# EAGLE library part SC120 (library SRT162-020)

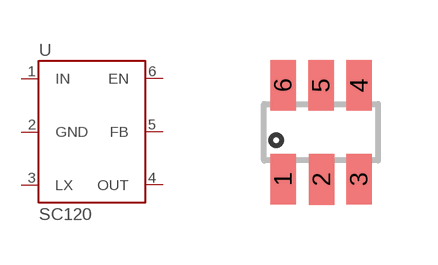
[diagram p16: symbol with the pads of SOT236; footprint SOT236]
Designator prefix U

## SC120  [SOT236]
1  IN  in
2  GND  pwr
3  LX  pas
4  OUT  out
5  FB  in
6  EN  in

## Footprint SOT236 (pad centres in mm)
smd 0.635 x 1.27: 1 -0.95,-1.175; 2 0.013,-1.185; 3 0.95,-1.175; 4 0.95,1.175; 5 0,1.175; 6 -0.95,1.175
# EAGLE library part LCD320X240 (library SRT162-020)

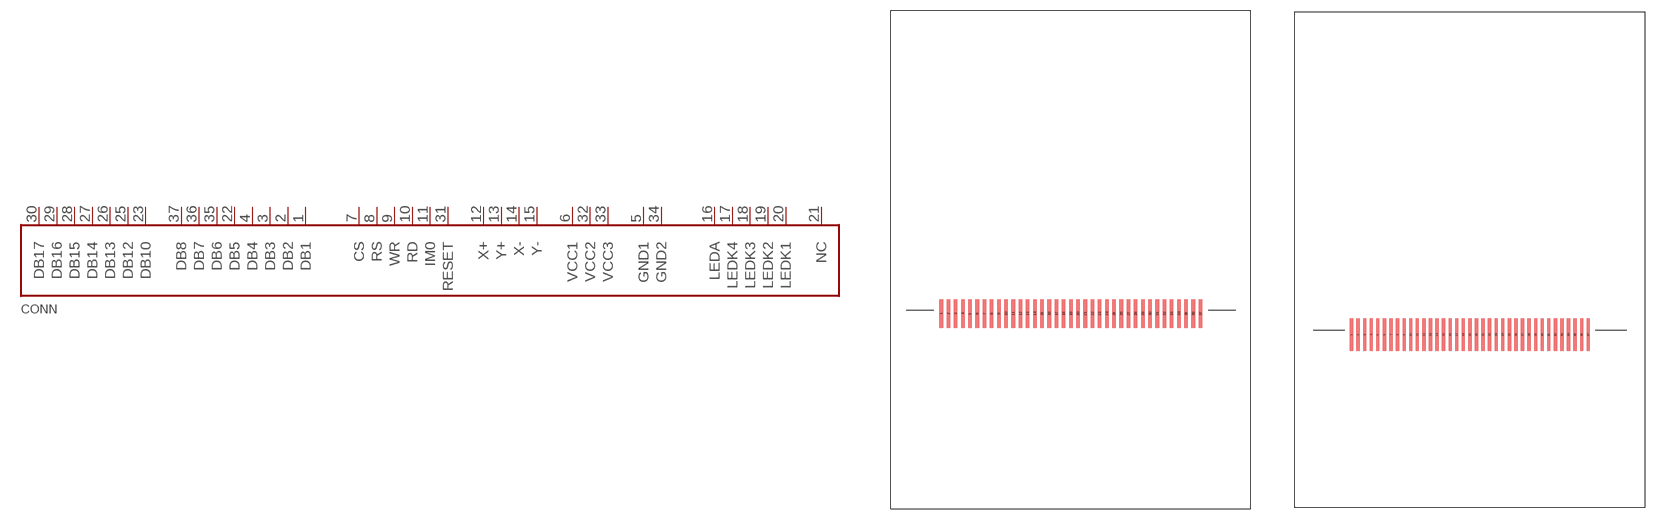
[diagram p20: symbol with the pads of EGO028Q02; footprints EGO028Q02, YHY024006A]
Designator prefix CONN

## LCD320X2402.8IN  [EGO028Q02]
1  DB1  pas
2  DB2  pas
3  DB3  pas
4  DB4  pas
5  GND1  pwr
6  VCC1  pwr
7  CS  pas
8  RS  pas
9  WR  pas
10  RD  pas
11  IM0  pas
12  X+  pas
13  Y+  pas
14  X-  pas
15  Y-  pas
16  LEDA  pas
17  LEDK4  pas
18  LEDK3  pas
19  LEDK2  pas
20  LEDK1  pas
21  NC  pas
22  DB5  pas
23  DB10  pas
24  DB11  pas
25  DB12  pas
26  DB13  pas
27  DB14  pas
28  DB15  pas
29  DB16  pas
30  DB17  pas
31  RESET  pas
32  VCC2  pwr
33  VCC3  pwr
34  GND2  pwr
35  DB6  pas
36  DB7  pas
37  DB8  pas

## LCD320X2402.4IN  [YHY024006A]
Pads as for EGO028Q02

## Footprint EGO028Q02 (pad centres in mm)
smd 0.5 x 4: 1 -18,0; 2 -17,0; 3 -16,0; 4 -15,0; 5 -14,0; 6 -13,0; 7 -12,0; 8 -11,0; 9 -10,0; 10 -9,0; 11 -8,0; 12 -7,0; 13 -6,0; 14 -5,0; 15 -4,0; 16 -3,0; 17 -2,0; 18 -1,0; 19 0,0; 20 1,0; 21 2,0; 22 3,0; 23 4,0; 24 5,0; 25 6,0; 26 7,0; 27 8,0; 28 9,0; 29 10,0; 30 11,0; 31 12,0; 32 13,0; 33 14,0; 34 15,0; 35 16,0; 36 17,0; 37 18,0

## Footprint YHY024006A (pad centres in mm)
smd 0.4 x 4: 1 -14.4,0; 2 -13.6,0; 3 -12.8,0; 4 -12,0; 5 -11.2,0; 6 -10.4,0; 7 -9.6,0; 8 -8.8,0; 9 -8,0; 10 -7.2,0; 11 -6.4,0; 12 -5.6,0; 13 -4.8,0; 14 -4,0; 15 -3.2,0; 16 -2.4,0; 17 -1.6,0; 18 -0.8,0; 19 0,0; 20 0.8,0; 21 1.6,0; 22 2.4,0; 23 3.2,0; 24 4,0; 25 4.8,0; 26 5.6,0; 27 6.4,0; 28 7.2,0; 29 8,0; 30 8.8,0; 31 9.6,0; 32 10.4,0; 33 11.2,0; 34 12,0; 35 12.8,0; 36 13.6,0; 37 14.4,0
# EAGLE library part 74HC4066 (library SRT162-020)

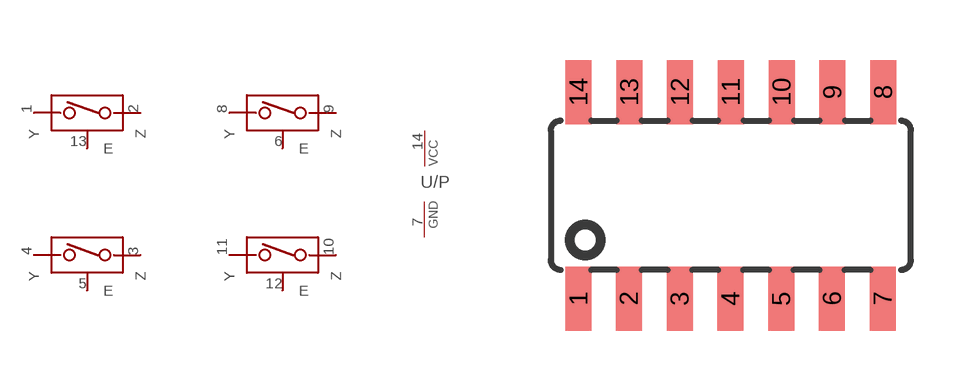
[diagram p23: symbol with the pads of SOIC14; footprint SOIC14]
Designator prefix U; gates /1=1/4_4066 /2=1/4_4066 /3=1/4_4066 /4=1/4_4066 /P=PWRN

## 74HC4066D  [SOIC14]
1  /1:Y  pas
2  /1:Z  pas
3  /2:Z  pas
4  /2:Y  pas
5  /2:E  in
6  /3:E  in
7  /P:GND  pwr
8  /3:Y  pas
9  /3:Z  pas
10  /4:Z  pas
11  /4:Y  pas
12  /4:E  in
13  /1:E  in
14  /P:VCC  pwr

## Footprint SOIC14 (pad centres in mm)
smd 0.65 x 1.6: 1 -5.715,-2.583; 2 -4.455,-2.583; 3 -3.185,-2.583; 4 -1.915,-2.583; 5 -0.645,-2.583; 6 0.625,-2.583; 7 1.895,-2.583; 8 1.905,2.583; 9 0.635,2.583; 10 -0.635,2.583; 11 -1.905,2.583; 12 -3.175,2.583; 13 -4.445,2.583; 14 -5.715,2.583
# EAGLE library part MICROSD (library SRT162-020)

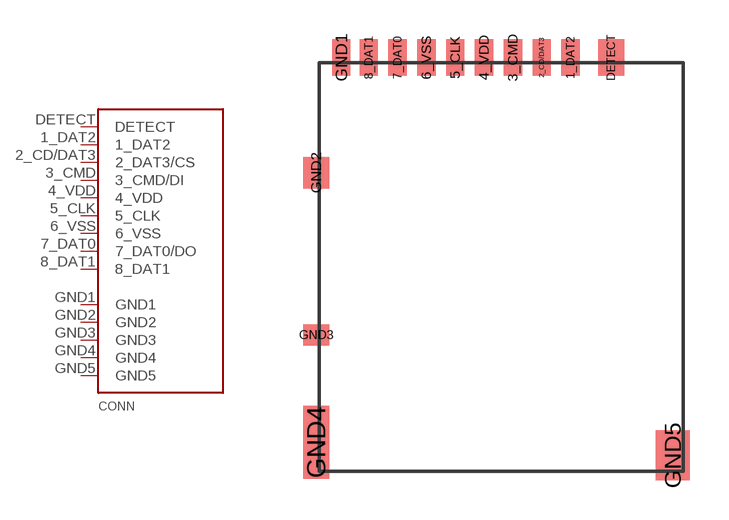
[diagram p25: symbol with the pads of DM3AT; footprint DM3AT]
Designator prefix CONN

## MICROSDDM3AT  [DM3AT]
1_DAT2  1_DAT2  pas
2_CD/DAT3  2_DAT3/CS  pas
3_CMD  3_CMD/DI  pas
4_VDD  4_VDD  pwr
5_CLK  5_CLK  pas
6_VSS  6_VSS  pwr
7_DAT0  7_DAT0/DO  pas
8_DAT1  8_DAT1  pas
DETECT  DETECT  pas
GND1  GND1  pas
GND2  GND2  pas
GND3  GND3  pas
GND4  GND4  pas
GND5  GND5  pas

## Footprint DM3AT (pad centres in mm)
smd 0.7 x 1.4: 1_DAT2 3.3,0.7; 2_CD/DAT3 2.2,0.7; 3_CMD 1.1,0.7; 4_VDD 0,0.7; 5_CLK -1.1,0.7; 6_VSS -2.2,0.7; 7_DAT0 -3.3,0.7; 8_DAT1 -4.4,0.7; GND1 -5.45,0.7
smd 1 x 1.4: DETECT 4.85,0.7
smd 1 x 1.2: GND2 -6.4,-3.7
smd 1 x 0.8: GND3 -6.4,-9.9
smd 1 x 2.8: GND4 -6.4,-14
smd 1.3 x 1.9: GND5 7.2,-14.5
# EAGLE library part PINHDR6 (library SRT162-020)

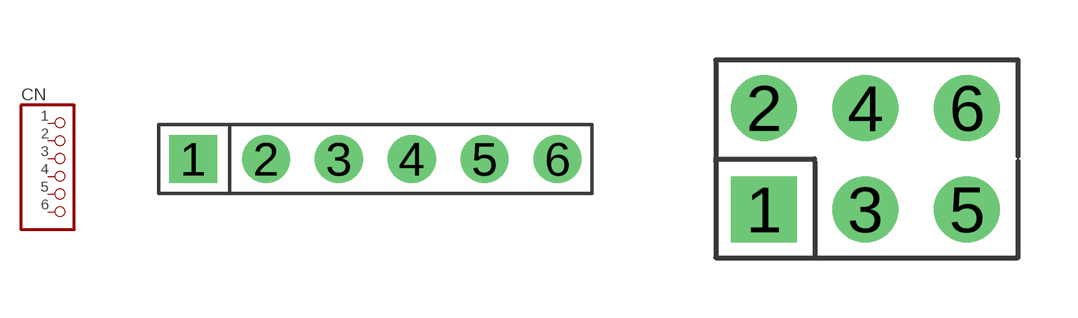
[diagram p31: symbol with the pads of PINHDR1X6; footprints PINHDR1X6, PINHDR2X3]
Designator prefix CN

## PINHDR6  [PINHDR1X6]
1  1  pas
2  2  pas
3  3  pas
4  4  pas
5  5  pas
6  6  pas

## PINHDR62X  [PINHDR2X3]
Pads as for PINHDR1X6

## PINHDR60.8  [PINHDR1X6_0.8]
Pads as for PINHDR1X6

## PINHDR60.8NM  [PINHDR1X6_0.8NM]
Pads as for PINHDR1X6

## PINHDR61.0  [PINHDR1X6_1.0]
Pads as for PINHDR1X6

## PINHDR61.0NM  [PINHDR1X6_1.0NM]
Pads as for PINHDR1X6

## PINHDR62MM  [PINHDR6_2MM]
Pads as for PINHDR1X6

## Footprint PINHDR1X6 (pad centres in mm)
drill 1.1 pad 1.676 square: 1 -6.35,0
drill 1.1 pad 1.676: 2 -3.81,0; 3 -1.27,0; 4 1.27,0; 5 3.81,0; 6 6.35,0

## Footprint PINHDR2X3 (pad centres in mm)
drill 1.1 square: 1 -2.54,-1.27
drill 1.1: 2 -2.54,1.27; 3 0,-1.27; 4 0,1.27; 5 2.54,-1.27; 6 2.54,1.27

## Footprint PINHDR1X6_0.8 (pad centres in mm)
drill 0.8 square: 1 -6.35,0
drill 0.8: 2 -3.81,0; 3 -1.27,0; 4 1.27,0; 5 3.81,0; 6 6.35,0

## Footprint PINHDR1X6_0.8NM (pad centres in mm)
drill 0.8: 1 -6.35,0; 2 -3.81,0; 3 -1.27,0; 4 1.27,0; 5 3.81,0; 6 6.35,0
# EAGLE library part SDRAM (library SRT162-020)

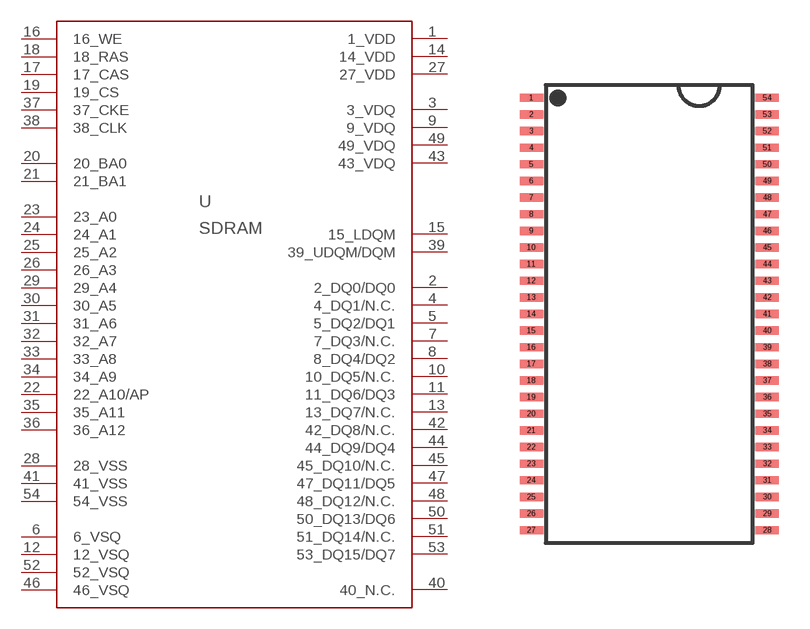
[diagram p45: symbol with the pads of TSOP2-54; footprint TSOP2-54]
Designator prefix U

## SDRAM  [TSOP2-54]
1  1_VDD  pwr
2  2_DQ0/DQ0
3  3_VDQ
4  4_DQ1/N.C.
5  5_DQ2/DQ1
6  6_VSQ  pwr
7  7_DQ3/N.C.
8  8_DQ4/DQ2
9  9_VDQ
10  10_DQ5/N.C.
11  11_DQ6/DQ3
12  12_VSQ  pwr
13  13_DQ7/N.C.
14  14_VDD  pwr
15  15_LDQM
16  16_WE  in
17  17_CAS  in
18  18_RAS  out
19  19_CS  in
20  20_BA0
21  21_BA1
22  22_A10/AP
23  23_A0
24  24_A1
25  25_A2
26  26_A3
27  27_VDD  pwr
28  28_VSS  pwr
29  29_A4
30  30_A5
31  31_A6
32  32_A7
33  33_A8
34  34_A9
35  35_A11
36  36_A12
37  37_CKE  in
38  38_CLK  in
39  39_UDQM/DQM  in
40  40_N.C.
41  41_VSS  pwr
42  42_DQ8/N.C.
43  43_VDQ
44  44_DQ9/DQ4
45  45_DQ10/N.C.
46  46_VSQ  pwr
47  47_DQ11/DQ5
48  48_DQ12/N.C.
49  49_VDQ
50  50_DQ13/DQ6
51  51_DQ14/N.C.
52  52_VSQ  pwr
53  53_DQ15/DQ7
54  54_VSS  pwr

## Footprint TSOP2-54 (pad centres in mm)
smd 1.1 x 0.4: 1 -5.68,10.4; 2 -5.68,9.6; 3 -5.68,8.8; 4 -5.68,8; 5 -5.68,7.2; 6 -5.68,6.4; 7 -5.68,5.6; 8 -5.68,4.8; 9 -5.68,4; 10 -5.68,3.2; 11 -5.68,2.4; 12 -5.68,1.6; 13 -5.68,0.8; 14 -5.68,0; 15 -5.68,-0.8; 16 -5.68,-1.6; 17 -5.68,-2.4; 18 -5.68,-3.2; 19 -5.68,-4; 20 -5.68,-4.8; 21 -5.68,-5.6; 22 -5.68,-6.4; 23 -5.68,-7.2; 24 -5.68,-8; 25 -5.68,-8.8; 26 -5.68,-9.6; 27 -5.68,-10.4; 28 5.68,-10.4; 29 5.68,-9.6; 30 5.68,-8.8; 31 5.68,-8; 32 5.68,-7.2; 33 5.68,-6.4; 34 5.68,-5.6; 35 5.68,-4.8; 36 5.68,-4; 37 5.68,-3.2; 38 5.68,-2.4; 39 5.68,-1.6; 40 5.68,-0.8; 41 5.68,0; 42 5.68,0.8; 43 5.68,1.6; 44 5.68,2.4; 45 5.68,3.2; 46 5.68,4; 47 5.68,4.8; 48 5.68,5.6; 49 5.68,6.4; 50 5.68,7.2; 51 5.68,8; 52 5.68,8.8; 53 5.68,9.6; 54 5.68,10.4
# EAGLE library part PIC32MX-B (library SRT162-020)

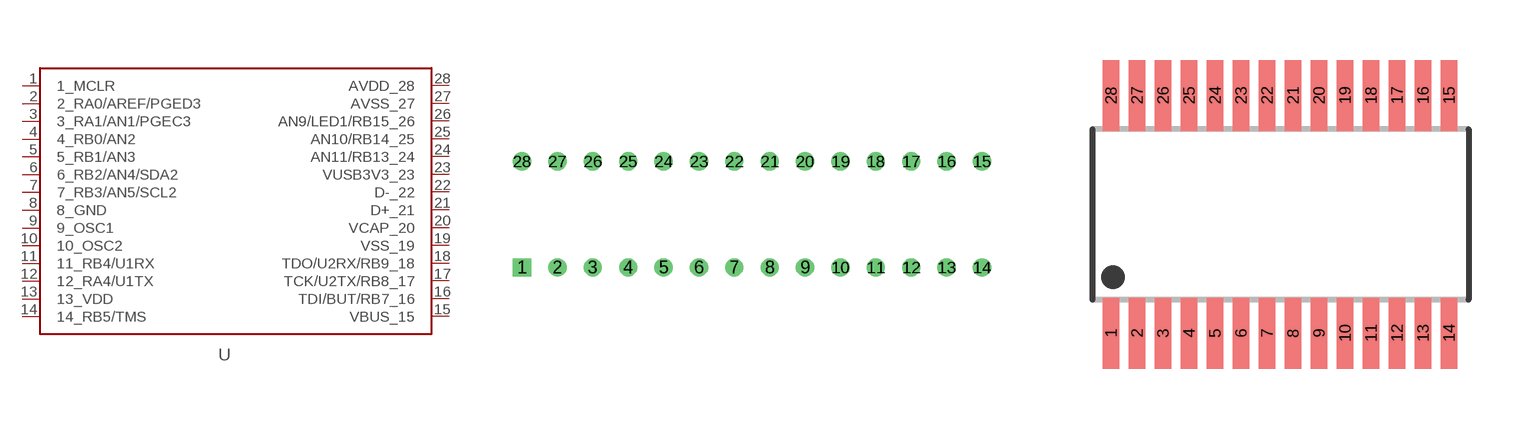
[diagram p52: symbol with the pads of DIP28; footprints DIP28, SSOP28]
Designator prefix U

## PIC32MX-BDIP  [DIP28]
1  1_MCLR  pas
2  2_RA0/AREF/PGED3  pas
3  3_RA1/AN1/PGEC3  pas
4  4_RB0/AN2  pas
5  5_RB1/AN3  pas
6  6_RB2/AN4/SDA2  pas
7  7_RB3/AN5/SCL2  pas
8  8_GND  pwr
9  9_OSC1  pas
10  10_OSC2  pas
11  11_RB4/U1RX  pas
12  12_RA4/U1TX  pas
13  13_VDD  pwr
14  14_RB5/TMS  pas
15  VBUS_15  pas
16  TDI/BUT/RB7_16  pas
17  TCK/U2TX/RB8_17  pas
18  TDO/U2RX/RB9_18  pas
19  VSS_19  pwr
20  VCAP_20  sup
21  D+_21  pas
22  D-_22  pas
23  VUSB3V3_23  pwr
24  AN11/RB13_24  pas
25  AN10/RB14_25  pas
26  AN9/LED1/RB15_26  pas
27  AVSS_27  pwr
28  AVDD_28  pwr

## PIC32MX-BSS  [SSOP28]
Pads as for DIP28

## PIC32MX-BQFN  [QFN28_0.65]
1  4_RB0/AN2  pas
2  5_RB1/AN3  pas
3  6_RB2/AN4/SDA2  pas
4  7_RB3/AN5/SCL2  pas
5  8_GND  pwr
6  9_OSC1  pas
7  10_OSC2  pas
8  11_RB4/U1RX  pas
9  12_RA4/U1TX  pas
10  13_VDD  pwr
11  14_RB5/TMS  pas
12  VBUS_15  pas
13  TDI/BUT/RB7_16  pas
14  TCK/U2TX/RB8_17  pas
15  TDO/U2RX/RB9_18  pas
16  VSS_19  pwr
17  VCAP_20  sup
18  D+_21  pas
19  D-_22  pas
20  VUSB3V3_23  pwr
21  AN11/RB13_24  pas
22  AN10/RB14_25  pas
23  AN9/LED1/RB15_26  pas
24  AVSS_27  pwr
25  AVDD_28  pwr
26  1_MCLR  pas
27  2_RA0/AREF/PGED3  pas
28  3_RA1/AN1/PGEC3  pas

## Footprint DIP28 (pad centres in mm)
drill 0.8 square: 1 -16.51,-3.81
drill 0.8: 2 -13.97,-3.81; 3 -11.43,-3.81; 4 -8.89,-3.81; 5 -6.35,-3.81; 6 -3.81,-3.81; 7 -1.27,-3.81; 8 1.27,-3.81; 9 3.81,-3.81; 10 6.35,-3.81; 11 8.89,-3.81; 12 11.43,-3.81; 13 13.97,-3.81; 14 16.51,-3.81; 15 16.51,3.81; 16 13.97,3.81; 17 11.43,3.81; 18 8.89,3.81; 19 6.35,3.81; 20 3.81,3.81; 21 1.27,3.81; 22 -1.27,3.81; 23 -3.81,3.81; 24 -6.35,3.81; 25 -8.89,3.81; 26 -11.43,3.81; 27 -13.97,3.81; 28 -16.51,3.81

## Footprint SSOP28 (pad centres in mm)
0.65mm pitch 28 pin
smd 0.42 x 1.78: 1 -4.26,-3.005; 2 -3.61,-3.005; 3 -2.96,-3.005; 4 -2.31,-3.005; 5 -1.66,-3.005; 6 -1.01,-3.005; 7 -0.36,-3.005; 8 0.29,-3.005; 9 0.94,-3.005; 10 1.59,-3.005; 11 2.24,-3.005; 12 2.89,-3.005; 13 3.54,-3.005; 14 4.19,-3.005; 15 4.19,2.945; 16 3.54,2.945; 17 2.89,2.945; 18 2.24,2.945; 19 1.59,2.945; 20 0.94,2.945; 21 0.29,2.945; 22 -0.36,2.945; 23 -1.01,2.945; 24 -1.66,2.945; 25 -2.31,2.945; 26 -2.96,2.945; 27 -3.61,2.945; 28 -4.26,2.945

## Footprint QFN28_0.65 (pad centres in mm)
smd 1.5 x 0.37: 1 -3.1,1.95; 2 -3.1,1.3; 3 -3.1,0.65; 4 -3.1,0; 5 -3.1,-0.65; 6 -3.1,-1.3; 7 -3.1,-1.95; 15 3.1,-1.95; 16 3.1,-1.3; 17 3.1,-0.65; 18 3.1,0; 19 3.1,0.65; 20 3.1,1.3; 21 3.1,1.95
smd 0.37 x 1.5: 8 -1.95,-3.1; 9 -1.3,-3.1; 10 -0.65,-3.1; 11 0,-3.1; 12 0.65,-3.1; 13 1.3,-3.1; 14 1.95,-3.1; 22 1.95,3.1; 23 1.3,3.1; 24 0.65,3.1; 25 0,3.1; 26 -0.65,3.1; 27 -1.3,3.1; 28 -1.95,3.1
drill 0.6 pad 1.6 octagon: PAD1 -0.9,0.9
drill 0.6 pad 1.6 square: PAD2 -0.9,-0.9; PAD3 0.9,-0.9; PAD4 0.9,0.9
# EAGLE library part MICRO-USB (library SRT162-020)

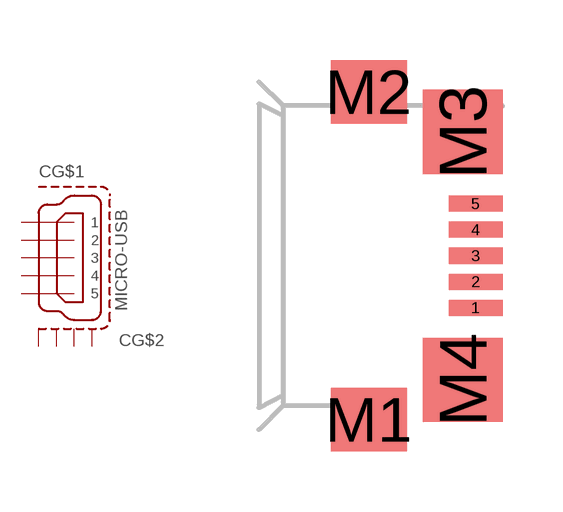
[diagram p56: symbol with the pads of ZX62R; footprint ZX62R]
Designator prefix C; gates G$1=MINI-USB G$2=USB-SHIELD

## MICRO-USB  [ZX62R]
1  G$1:1
2  G$1:2
3  G$1:3
4  G$1:4
5  G$1:5
M1  G$2:S1  pas
M2  G$2:S2  pas
M3  G$2:S3  pas
M4  G$2:S4  pas

## Footprint ZX62R (pad centres in mm)
smd 1.35 x 0.4: 1 2.675,-1.3; 2 2.675,-0.65; 3 2.675,0; 4 2.675,0.65; 5 2.675,1.3
smd 1.9 x 1.6: M1 0,-4.1; M2 0,4.1
smd 2 x 2.1: M3 2.35,3.1; M4 2.35,-3.1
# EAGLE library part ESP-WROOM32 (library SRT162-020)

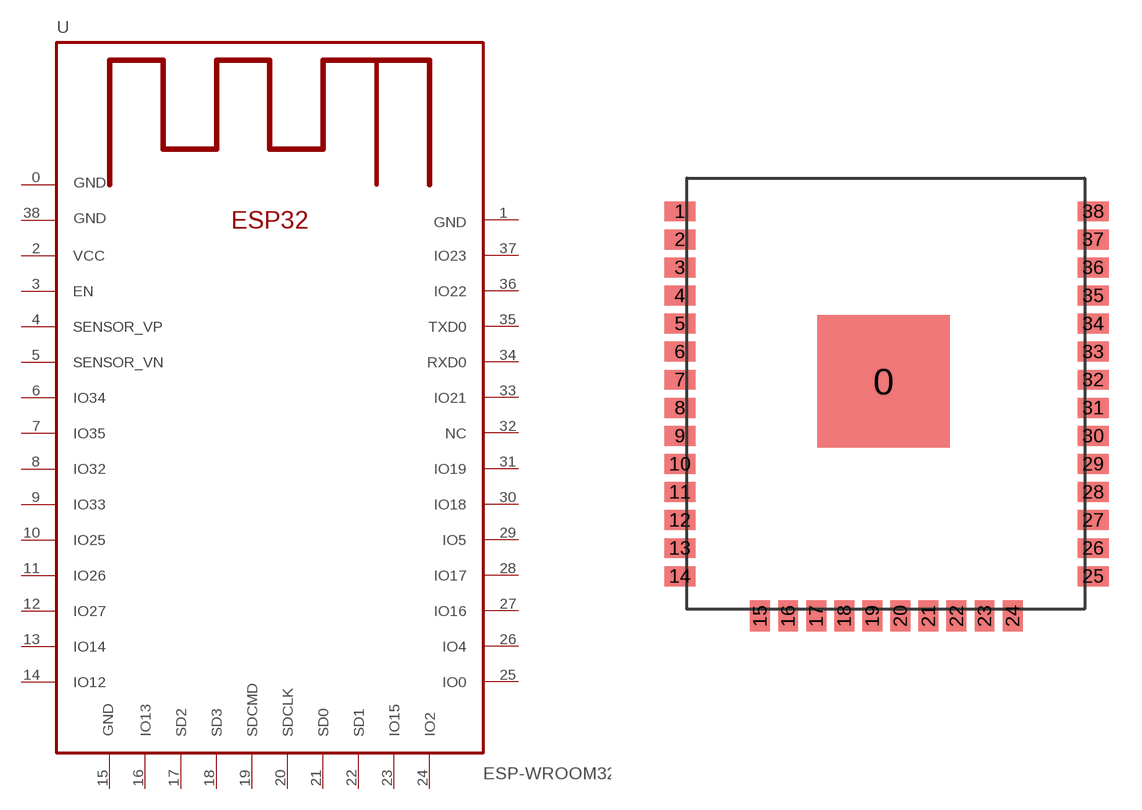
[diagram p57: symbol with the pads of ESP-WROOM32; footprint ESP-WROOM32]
Designator prefix U

## ESP-WROOM32  [ESP-WROOM32]
0  GND  pwr
1  GND  pwr
2  VCC  pwr
3  EN
4  SENSOR_VP
5  SENSOR_VN
6  IO34
7  IO35
8  IO32
9  IO33
10  IO25
11  IO26
12  IO27
13  IO14
14  IO12
15  GND  pwr
16  IO13
17  SD2
18  SD3
19  SDCMD
20  SDCLK
21  SD0
22  SD1
23  IO15
24  IO2
25  IO0
26  IO4
27  IO16
28  IO17
29  IO5
30  IO18
31  IO19
32  NC
33  IO21
34  RXD0
35  TXD0
36  IO22
37  IO23
38  GND  pwr

## Footprint ESP-WROOM32 (pad centres in mm)
smd 6 x 6: 0 9.9,12.3
smd 1.4 x 0.9: 1 0.68,19.99; 2 0.68,18.72; 3 0.68,17.45; 4 0.68,16.18; 5 0.68,14.91; 6 0.68,13.64; 7 0.68,12.37; 8 0.68,11.1; 9 0.68,9.83; 10 0.68,8.56; 11 0.68,7.29; 12 0.68,6.02; 13 0.68,4.75; 14 0.68,3.48; 25 19.38,3.48; 26 19.38,4.75; 27 19.38,6.02; 28 19.38,7.29; 29 19.38,8.56; 30 19.38,9.83; 31 19.38,11.1; 32 19.38,12.37; 33 19.38,13.64; 34 19.38,14.91; 35 19.38,16.18; 36 19.38,17.45; 37 19.38,18.72; 38 19.38,19.99
smd 0.9 x 1.4: 15 4.31,1.68; 16 5.58,1.68; 17 6.85,1.68; 18 8.12,1.68; 19 9.39,1.68; 20 10.66,1.68; 21 11.93,1.68; 22 13.2,1.68; 23 14.47,1.68; 24 15.74,1.68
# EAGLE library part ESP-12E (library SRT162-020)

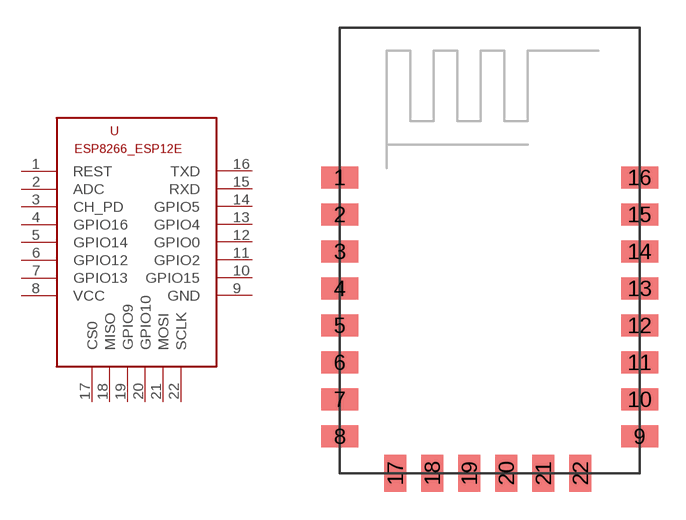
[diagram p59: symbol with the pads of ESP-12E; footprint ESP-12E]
Designator prefix -

## ESP-12E  [ESP-12E]
1  REST
2  ADC
3  CH_PD
4  GPIO16
5  GPIO14
6  GPIO12
7  GPIO13
8  VCC
9  GND
10  GPIO15
11  GPIO2
12  GPIO0
13  GPIO4
14  GPIO5
15  RXD
16  TXD
17  CS0
18  MISO
19  GPIO9
20  GPIO10
21  MOSI
22  SCLK

## Footprint ESP-12E (pad centres in mm)
smd 2 x 1.2: 1 -7.62,5.84; 2 -7.62,3.84; 3 -7.62,1.84; 4 -7.62,-0.16; 5 -7.62,-2.16; 6 -7.62,-4.16; 7 -7.62,-6.16; 8 -7.62,-8.16; 9 8.58,-8.16; 10 8.58,-6.16; 11 8.58,-4.16; 12 8.58,-2.16; 13 8.58,-0.16; 14 8.58,1.84; 15 8.58,3.84; 16 8.58,5.84
smd 1.2 x 2: 17 -4.62,-10.16; 18 -2.62,-10.16; 19 -0.62,-10.16; 20 1.38,-10.16; 21 3.38,-10.16; 22 5.38,-10.16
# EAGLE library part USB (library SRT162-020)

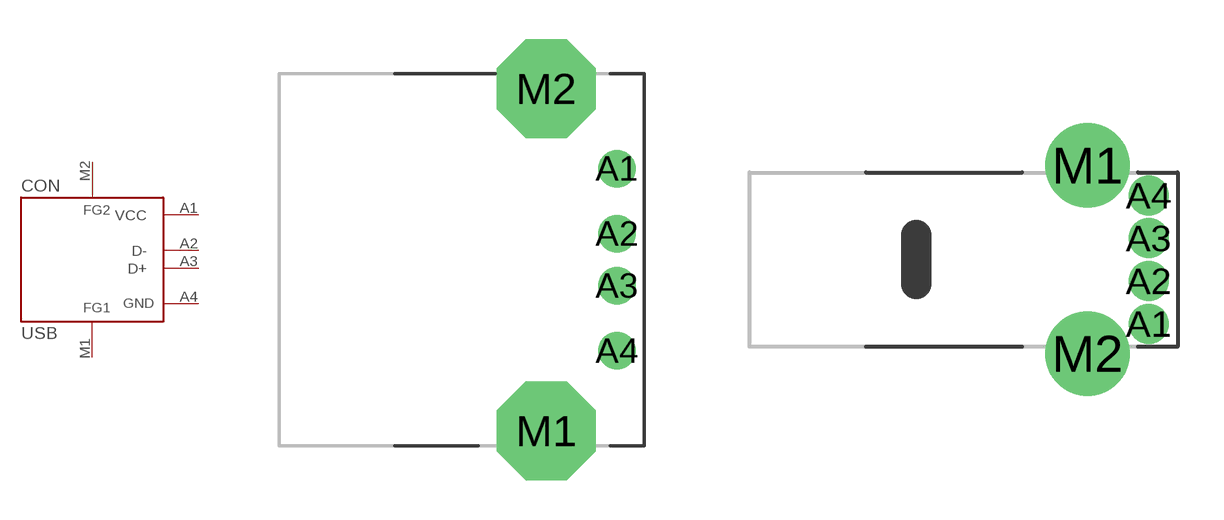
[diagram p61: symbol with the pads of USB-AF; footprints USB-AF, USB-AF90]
Designator prefix CON

## USB-B  [USB-AF]
A1  VCC  pas
A2  D-
A3  D+
A4  GND  pas
M1  GND  pas
M2  GND  pas

## USB90  [USB-AF90]
Pads as for USB-AF

## Footprint USB-AF (pad centres in mm)
drill 0.93: A1 3.175,3.5; A2 3.175,1; A3 3.175,-1; A4 3.175,-3.5
drill 2.4 pad 3.81 octagon: M1 0.465,-6.57; M2 0.465,6.57

## Footprint USB-AF90 (pad centres in mm)
drill 0.8 pad 1.156: A1 2,-2.1; A2 2,-0.7; A3 2,0.7; A4 2,2.1
drill 1.84 pad 2.348: M1 0,3.08; M2 0,-3.08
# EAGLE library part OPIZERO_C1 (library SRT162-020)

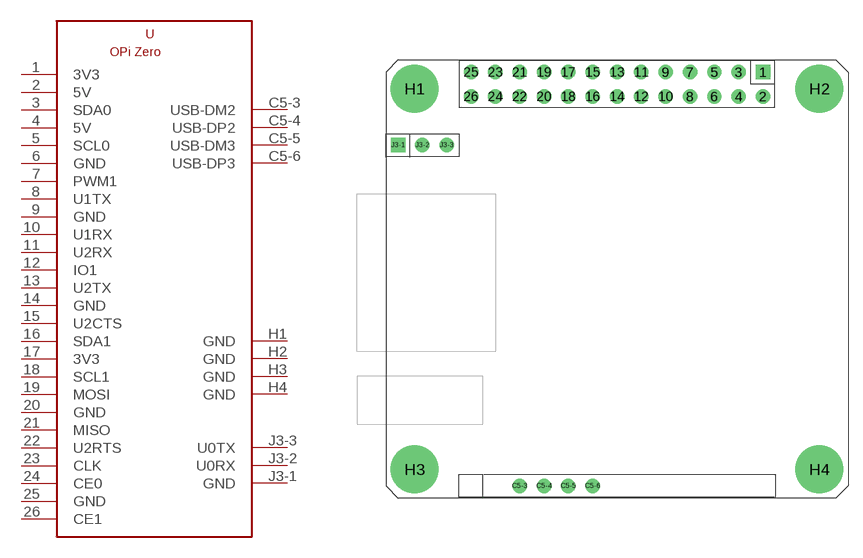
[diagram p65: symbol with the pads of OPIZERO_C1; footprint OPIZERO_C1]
Designator prefix -

## OPIZERO_C1  [OPIZERO_C1]
1  3V3
2  5V  pwr
3  SDA0
4  5V  pwr
5  SCL0
6  GND  pwr
7  PWM1
8  U1TX
9  GND  pwr
10  U1RX
11  U2RX
12  IO1
13  U2TX
14  GND  pwr
15  U2CTS
16  SDA1
17  3V3
18  SCL1
19  MOSI
20  GND  pwr
21  MISO
22  U2RTS
23  CLK
24  CE0
25  GND  pwr
26  CE1
C5-3  USB-DM2
C5-4  USB-DP2
C5-5  USB-DM3
C5-6  USB-DP3
H1  GND  pwr
H2  GND  pwr
H3  GND  pwr
H4  GND  pwr
J3-1  GND  pwr
J3-2  U0RX
J3-3  U0TX

## Footprint OPIZERO_C1 (pad centres in mm)
drill 1 square: 1 15.24,21.59; J3-1 -22.86,13.97
drill 1: 2 15.24,19.05; 3 12.7,21.59; 4 12.7,19.05; 5 10.16,21.59; 6 10.16,19.05; 7 7.62,21.59; 8 7.62,19.05; 9 5.08,21.59; 10 5.08,19.05; 11 2.54,21.59; 12 2.54,19.05; 13 0,21.59; 14 0,19.05; 15 -2.54,21.59; 16 -2.54,19.05; 17 -5.08,21.59; 18 -5.08,19.05; 19 -7.62,21.59; 20 -7.62,19.05; 21 -10.16,21.59; 22 -10.16,19.05; 23 -12.7,21.59; 24 -12.7,19.05; 25 -15.24,21.59; 26 -15.24,19.05; C5-3 -10.16,-21.59; C5-4 -7.62,-21.59; C5-5 -5.08,-21.59; C5-6 -2.54,-21.59; J3-2 -20.32,13.97; J3-3 -17.78,13.97
drill 3.3 pad 5: H1 -21.13,19.86; H2 21.13,19.86; H3 -21.13,-19.86; H4 21.13,-19.86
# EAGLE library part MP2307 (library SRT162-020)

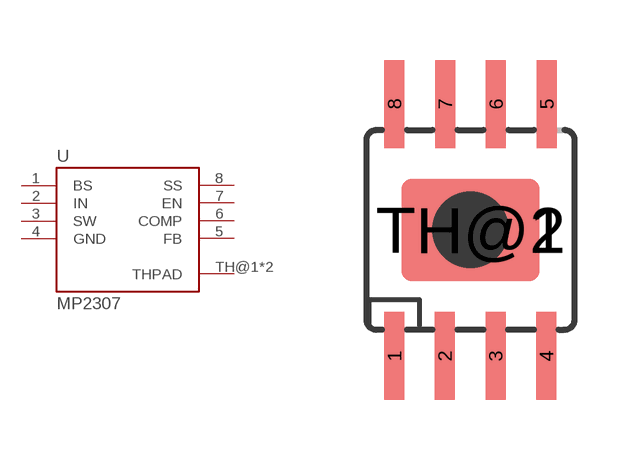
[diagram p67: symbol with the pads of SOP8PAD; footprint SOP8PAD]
Designator prefix -

## MP2307  [SOP8PAD]
1  BS
2  IN
3  SW
4  GND  pas
5  FB
6  COMP
7  EN
8  SS
TH@1  THPAD  pas
TH@2  THPAD  pas

## Footprint SOP8PAD (pad centres in mm)
smd 0.5 x 2.2: 1 -1.905,-3.154; 2 -0.645,-3.154; 3 0.625,-3.154; 4 1.895,-3.154; 5 1.905,3.154; 6 0.635,3.154; 7 -0.635,3.154; 8 -1.905,3.154
smd 3.454 x 2.565: TH@1 0,0
smd 3.454 x 2.565 bottom: TH@2 0,0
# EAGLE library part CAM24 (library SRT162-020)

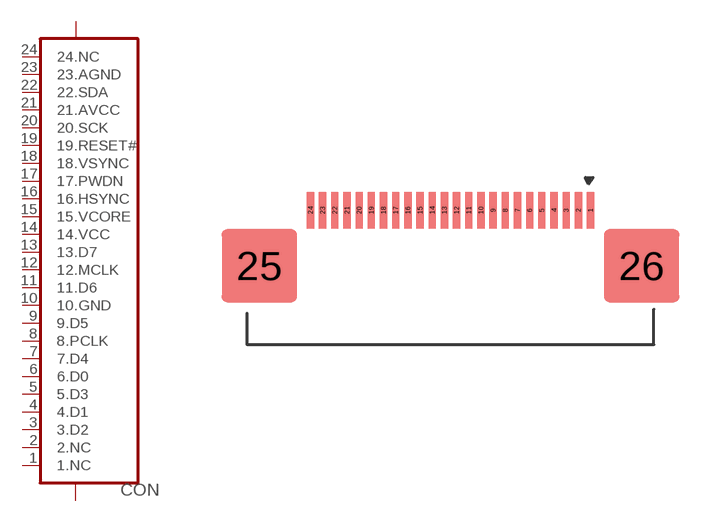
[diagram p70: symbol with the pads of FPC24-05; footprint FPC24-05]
Designator prefix CON

## CAM24  [FPC24-05]
1  1.NC  pas
2  2.NC  pas
3  3.D2  pas
4  4.D1  pas
5  5.D3  pas
6  6.D0  pas
7  7.D4  pas
8  8.PCLK  pas
9  9.D5  pas
10  10.GND  pas
11  11.D6  pas
12  12.MCLK  pas
13  13.D7  pas
14  14.VCC  pas
15  15.VCORE  pas
16  16.HSYNC  pas
17  17.PWDN  pas
18  18.VSYNC  pas
19  19.RESET#  pas
20  20.SCK  pas
21  21.AVCC  pas
22  22.SDA  pas
23  23.AGND  pas
24  24.NC  pas
25  25  pas
26  26  pas

## Footprint FPC24-05 (pad centres in mm)
smd 0.3 x 1.5: 1 5.75,-0.7; 2 5.25,-0.7; 3 4.75,-0.7; 4 4.25,-0.7; 5 3.75,-0.7; 6 3.25,-0.7; 7 2.75,-0.7; 8 2.25,-0.7; 9 1.75,-0.7; 10 1.25,-0.7; 11 0.75,-0.7; 12 0.25,-0.7; 13 -0.25,-0.7; 14 -0.75,-0.7; 15 -1.25,-0.7; 16 -1.75,-0.7; 17 -2.25,-0.7; 18 -2.75,-0.7; 19 -3.25,-0.7; 20 -3.75,-0.7; 21 -4.25,-0.7; 22 -4.75,-0.7; 23 -5.25,-0.7; 24 -5.75,-0.7
smd 3.1 x 3: 25 -7.85,-2.98; 26 7.85,-2.98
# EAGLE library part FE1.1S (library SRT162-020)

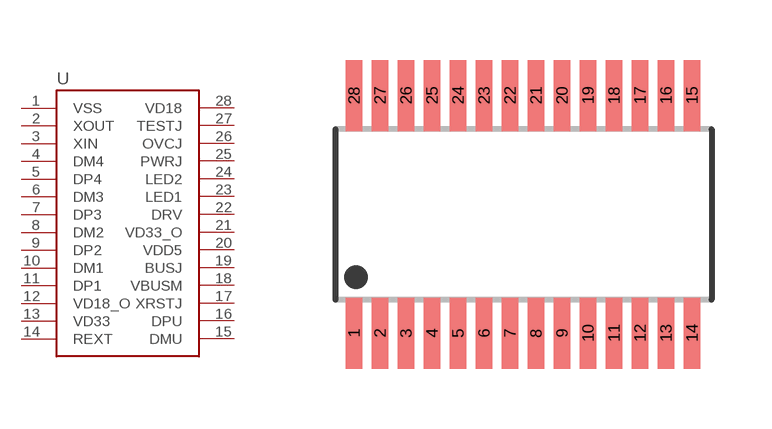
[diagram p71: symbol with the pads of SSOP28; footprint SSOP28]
Designator prefix U

## FE1.1S  [SSOP28]
1  VSS
2  XOUT
3  XIN
4  DM4
5  DP4
6  DM3
7  DP3
8  DM2
9  DP2
10  DM1
11  DP1
12  VD18_O
13  VD33
14  REXT
15  DMU
16  DPU
17  XRSTJ
18  VBUSM
19  BUSJ
20  VDD5
21  VD33_O
22  DRV
23  LED1
24  LED2
25  PWRJ
26  OVCJ
27  TESTJ
28  VD18

## Footprint SSOP28 (pad centres in mm)
0.65mm pitch 28 pin
smd 0.42 x 1.78: 1 -4.26,-3.005; 2 -3.61,-3.005; 3 -2.96,-3.005; 4 -2.31,-3.005; 5 -1.66,-3.005; 6 -1.01,-3.005; 7 -0.36,-3.005; 8 0.29,-3.005; 9 0.94,-3.005; 10 1.59,-3.005; 11 2.24,-3.005; 12 2.89,-3.005; 13 3.54,-3.005; 14 4.19,-3.005; 15 4.19,2.945; 16 3.54,2.945; 17 2.89,2.945; 18 2.24,2.945; 19 1.59,2.945; 20 0.94,2.945; 21 0.29,2.945; 22 -0.36,2.945; 23 -1.01,2.945; 24 -1.66,2.945; 25 -2.31,2.945; 26 -2.96,2.945; 27 -3.61,2.945; 28 -4.26,2.945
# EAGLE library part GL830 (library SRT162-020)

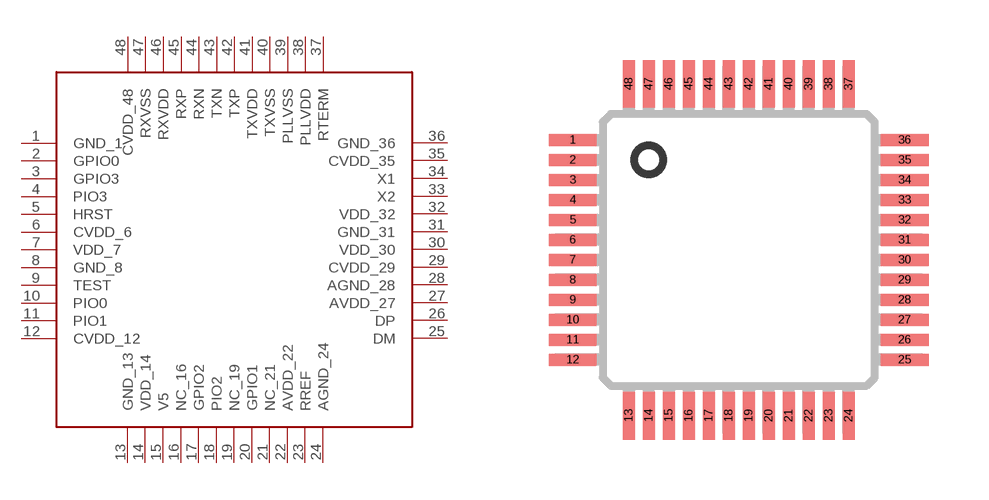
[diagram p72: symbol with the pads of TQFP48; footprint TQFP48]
Designator prefix U

## GL830  [TQFP48]
1  GND_1
2  GPIO0
3  GPIO3
4  PIO3
5  HRST
6  CVDD_6
7  VDD_7
8  GND_8
9  TEST
10  PIO0
11  PIO1
12  CVDD_12
13  GND_13
14  VDD_14
15  V5
16  NC_16
17  GPIO2
18  PIO2
19  NC_19
20  GPIO1
21  NC_21
22  AVDD_22
23  RREF
24  AGND_24
25  DM
26  DP
27  AVDD_27
28  AGND_28
29  CVDD_29
30  VDD_30
31  GND_31
32  VDD_32
33  X2
34  X1
35  CVDD_35
36  GND_36
37  RTERM
38  PLLVDD
39  PLLVSS
40  TXVSS
41  TXVDD
42  TXP
43  TXN
44  RXN
45  RXP
46  RXVDD
47  RXVSS
48  CVDD_48

## Footprint TQFP48 (pad centres in mm)
smd 1.2 x 0.3: 1 -4.15,2.75; 2 -4.15,2.25; 3 -4.15,1.75; 4 -4.15,1.25; 5 -4.15,0.75; 6 -4.15,0.25; 7 -4.15,-0.25; 8 -4.15,-0.75; 9 -4.15,-1.25; 10 -4.15,-1.75; 11 -4.15,-2.25; 12 -4.15,-2.75; 25 4.15,-2.75; 26 4.15,-2.25; 27 4.15,-1.75; 28 4.15,-1.25; 29 4.15,-0.75; 30 4.15,-0.25; 31 4.15,0.25; 32 4.15,0.75; 33 4.15,1.25; 34 4.15,1.75; 35 4.15,2.25; 36 4.15,2.75
smd 0.3 x 1.2: 13 -2.75,-4.15; 14 -2.25,-4.15; 15 -1.75,-4.15; 16 -1.25,-4.15; 17 -0.75,-4.15; 18 -0.25,-4.15; 19 0.25,-4.15; 20 0.75,-4.15; 21 1.25,-4.15; 22 1.75,-4.15; 23 2.25,-4.15; 24 2.75,-4.15; 37 2.75,4.15; 38 2.25,4.15; 39 1.75,4.15; 40 1.25,4.15; 41 0.75,4.15; 42 0.25,4.15; 43 -0.25,4.15; 44 -0.75,4.15; 45 -1.25,4.15; 46 -1.75,4.15; 47 -2.25,4.15; 48 -2.75,4.15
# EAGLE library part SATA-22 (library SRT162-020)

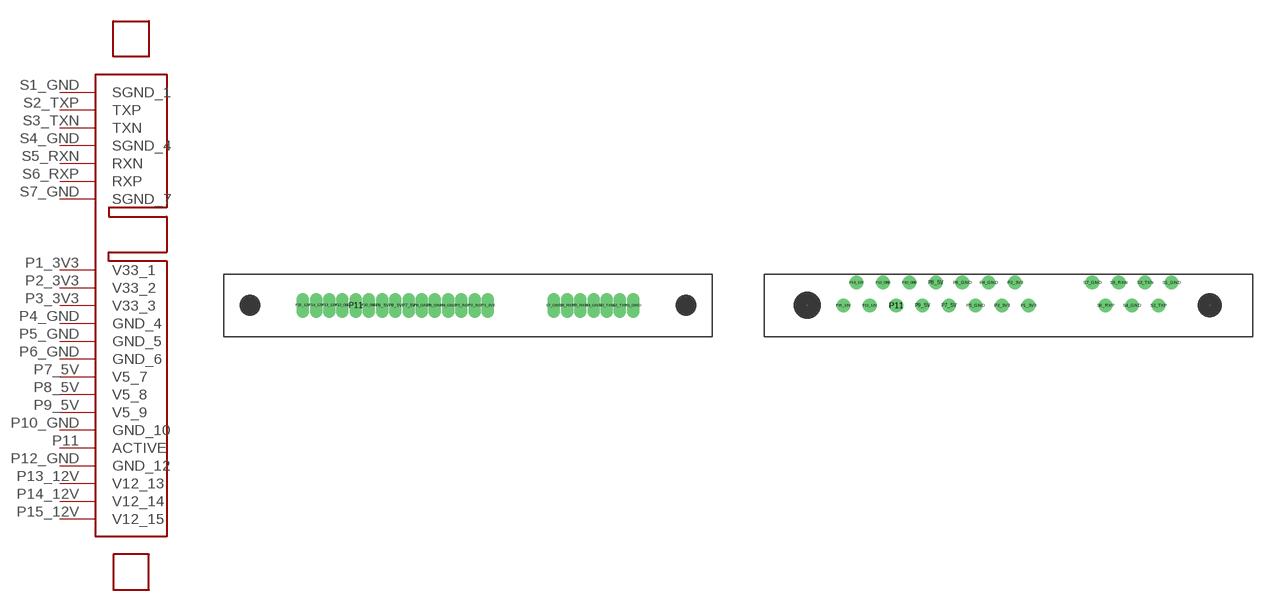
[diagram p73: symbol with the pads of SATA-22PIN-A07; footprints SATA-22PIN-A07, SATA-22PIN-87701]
Designator prefix CON

## SATA-22-07  [SATA-22PIN-A07]
P1_3V3  V33_1
P2_3V3  V33_2
P3_3V3  V33_3
P4_GND  GND_4
P5_GND  GND_5
P6_GND  GND_6
P7_5V  V5_7
P8_5V  V5_8
P9_5V  V5_9
P10_GND  GND_10
P11  ACTIVE
P12_GND  GND_12
P13_12V  V12_13
P14_12V  V12_14
P15_12V  V12_15
S1_GND  SGND_1
S2_TXP  TXP
S3_TXN  TXN
S4_GND  SGND_4
S5_RXN  RXN
S6_RXP  RXP
S7_GND  SGND_7

## SATA-22  [SATA-22PIN-87701]
Pads as for SATA-22PIN-A07

## SATA-2279  [SATA-22PIN-87779]
Pads as for SATA-22PIN-A07

## Footprint SATA-22PIN-A07 (pad centres in mm)
drill 0.7 pad 1.081 long: P1_3V3 0,0; P2_3V3 -1.27,0; P3_3V3 -2.54,0; P4_GND -3.81,0; P5_GND -5.08,0; P6_GND -6.35,0; P7_5V -7.62,0; P8_5V -8.89,0; P9_5V -10.16,0; P10_GND -11.43,0; P11 -12.7,0; P12_GND -13.97,0; P13_12V -15.24,0; P14_12V -16.51,0; P15_12V -17.78,0; S1_GND 13.97,0; S2_TXP 12.7,0; S3_TXN 11.43,0; S4_GND 10.16,0; S5_RXN 8.89,0; S6_RXP 7.62,0; S7_GND 6.35,0

## Footprint SATA-22PIN-87701 (pad centres in mm)
drill 0.8 pad 1.081: P1_3V3 0,0; P2_3V3 -1.27,2.2; P3_3V3 -2.54,0; P4_GND -3.81,2.2; P5_GND -5.08,0; P6_GND -6.35,2.2; P7_5V -7.62,0; P8_5V -8.89,2.2; P9_5V -10.16,0; P10_GND -11.43,2.2; P11 -12.7,0; P12_GND -13.97,2.2; P13_12V -15.24,0; P14_12V -16.51,2.2; P15_12V -17.78,0; S1_GND 13.77,2.2; S2_TXP 12.5,0; S3_TXN 11.23,2.2; S4_GND 9.96,0; S5_RXN 8.69,2.2; S6_RXP 7.42,0; S7_GND 6.15,2.2

## Footprint SATA-22PIN-87779 (pad centres in mm)
drill 0.7 pad 1.081 long: P1_3V3 0,0; P2_3V3 -1.27,0; P3_3V3 -2.54,0; P4_GND -3.81,0; P5_GND -5.08,0; P6_GND -6.35,0; P7_5V -7.62,0; P8_5V -8.89,0; P9_5V -10.16,0; P10_GND -11.43,0; P11 -12.7,0; P12_GND -13.97,0; P13_12V -15.24,0; P14_12V -16.51,0; P15_12V -17.78,0; S1_GND 13.77,0; S2_TXP 12.5,0; S3_TXN 11.23,0; S4_GND 9.96,0; S5_RXN 8.69,0; S6_RXP 7.42,0; S7_GND 6.15,0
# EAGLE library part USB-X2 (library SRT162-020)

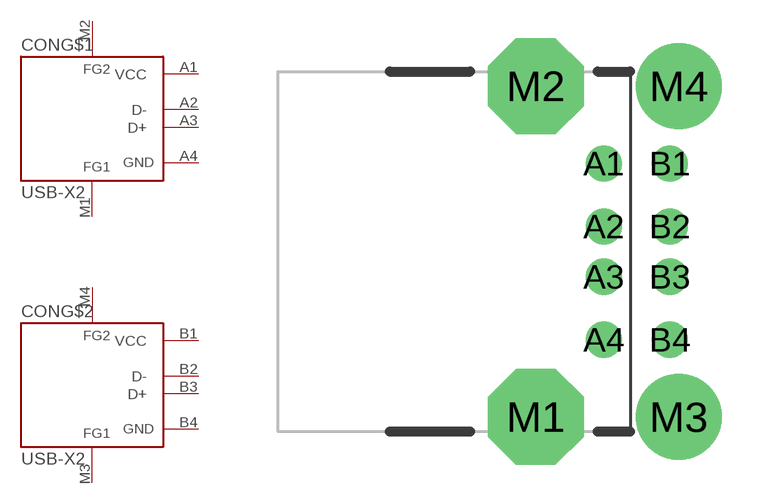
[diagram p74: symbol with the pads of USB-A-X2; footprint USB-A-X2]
Designator prefix CON; gates G$1=USB G$2=USB

## USB-X2  [USB-A-X2]
A1  G$1:VCC  pas
A2  G$1:D-
A3  G$1:D+
A4  G$1:GND  pas
B1  G$2:VCC  pas
B2  G$2:D-
B3  G$2:D+
B4  G$2:GND  pas
M1  G$1:GND  pas
M2  G$1:GND  pas
M3  G$2:GND  pas
M4  G$2:GND  pas

## Footprint USB-A-X2 (pad centres in mm)
drill 0.93 pad 1.438: A1 3.175,3.5; A2 3.175,1; A3 3.175,-1; A4 3.175,-3.5; B1 5.795,3.5; B2 5.795,1; B3 5.795,-1; B4 5.795,-3.5
drill 2.4 pad 3.81 octagon: M1 0.465,-6.57; M2 0.465,6.57
drill 2.4 pad 2.918: M3 6.145,-6.57
drill 2.4 pad 2.908: M4 6.145,6.57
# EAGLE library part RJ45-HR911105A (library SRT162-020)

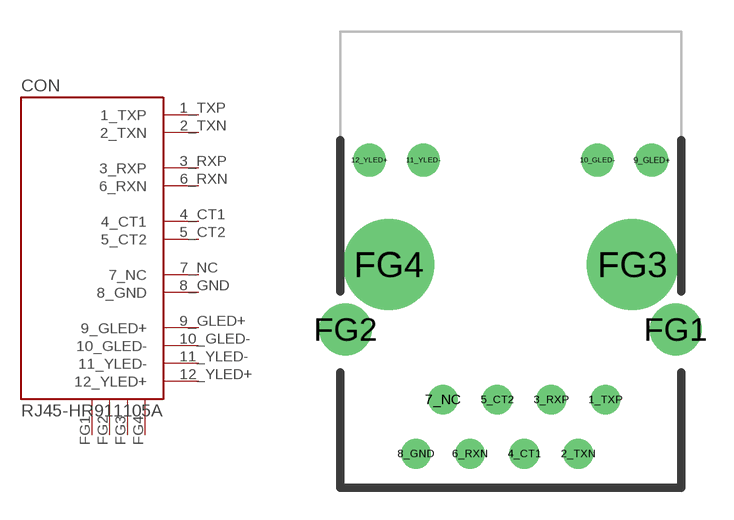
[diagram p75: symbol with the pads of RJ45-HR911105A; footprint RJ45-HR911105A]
Designator prefix CON

## RJ45-HR911105A  [RJ45-HR911105A]
1_TXP  1_TXP
2_TXN  2_TXN
3_RXP  3_RXP
4_CT1  4_CT1
5_CT2  5_CT2
6_RXN  6_RXN
7_NC  7_NC  pas
8_GND  8_GND  pas
9_GLED+  9_GLED+
10_GLED-  10_GLED-
11_YLED-  11_YLED-
12_YLED+  12_YLED+
FG1  GND  pas
FG2  GND  pas
FG3  GND  pas
FG4  GND  pas

## Footprint RJ45-HR911105A (pad centres in mm)
drill 0.89: 1_TXP 4.45,-6.35; 2_TXN 3.18,-8.89; 3_RXP 1.91,-6.35; 4_CT1 0.64,-8.89; 5_CT2 -0.63,-6.35; 6_RXN -1.9,-8.89; 7_NC -3.17,-6.35; 8_GND -4.44,-8.89
drill 1.02 pad 1.528: 9_GLED+ 6.625,4.9; 10_GLED- 4.085,4.9; 11_YLED- -4.085,4.9; 12_YLED+ -6.625,4.9
drill 1.63: FG1 7.745,-3.05; FG2 -7.745,-3.05
drill 3.25 pad 3.75: FG3 5.715,0; FG4 -5.715,0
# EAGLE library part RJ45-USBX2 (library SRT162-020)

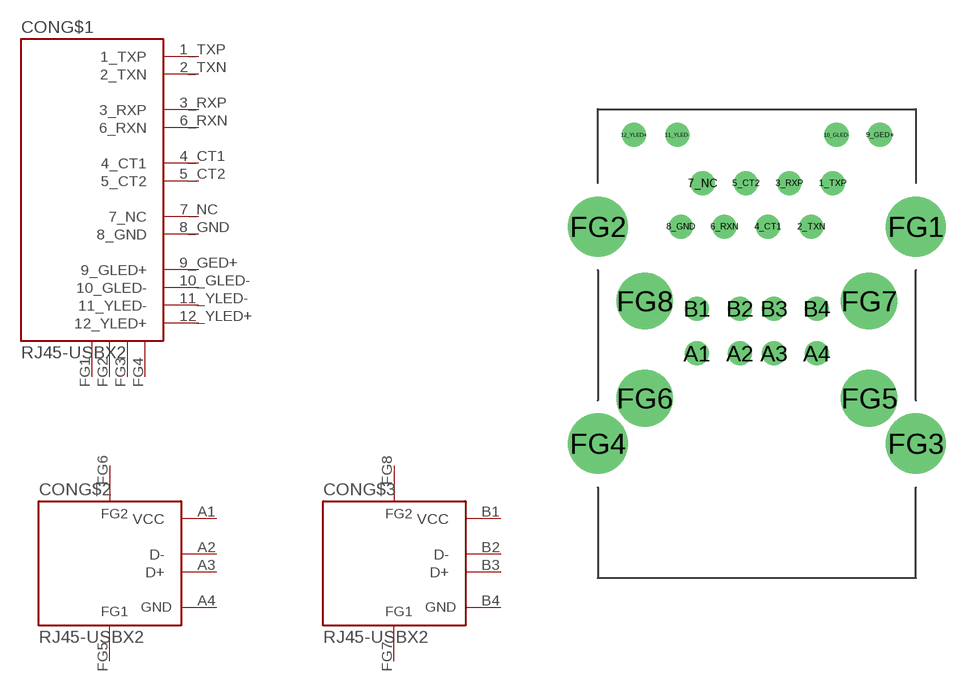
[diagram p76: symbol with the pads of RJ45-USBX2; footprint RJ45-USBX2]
Designator prefix CON; gates G$1=RJ45-100M G$2=USB G$3=USB

## RJ45-USBX2  [RJ45-USBX2]
1_TXP  G$1:1_TXP
2_TXN  G$1:2_TXN
3_RXP  G$1:3_RXP
4_CT1  G$1:4_CT1
5_CT2  G$1:5_CT2
6_RXN  G$1:6_RXN
7_NC  G$1:7_NC  pas
8_GND  G$1:8_GND  pas
9_GED+  G$1:9_GLED+
10_GLED-  G$1:10_GLED-
11_YLED-  G$1:11_YLED-
12_YLED+  G$1:12_YLED+
A1  G$2:VCC  pas
A2  G$2:D-
A3  G$2:D+
A4  G$2:GND  pas
B1  G$3:VCC  pas
B2  G$3:D-
B3  G$3:D+
B4  G$3:GND  pas
FG1  G$1:GND  pas
FG2  G$1:GND  pas
FG3  G$1:GND  pas
FG4  G$1:GND  pas
FG5  G$2:GND  pas
FG6  G$2:GND  pas
FG7  G$3:GND  pas
FG8  G$3:GND  pas

## Footprint RJ45-USBX2 (pad centres in mm)
drill 0.9: 1_TXP 4.445,2.54; 2_TXN 3.175,0; 3_RXP 1.905,2.54; 4_CT1 0.635,0; 5_CT2 -0.635,2.54; 6_RXN -1.905,0; 7_NC -3.175,2.54; 8_GND -4.445,0; 9_GED+ 7.2,5.37; 10_GLED- 4.66,5.37; 11_YLED- -4.66,5.37; 12_YLED+ -7.2,5.37; A1 -3.5,-7.41; A2 -1,-7.41; A3 1,-7.41; A4 3.5,-7.41; B1 -3.5,-4.79; B2 -1,-4.79; B3 1,-4.79; B4 3.5,-4.79
drill 2.5: FG1 9.3,0; FG2 -9.3,0; FG3 9.3,-12.68; FG4 -9.3,-12.68
drill 2.3: FG5 6.565,-10.03; FG6 -6.565,-10.03; FG7 6.565,-4.35; FG8 -6.565,-4.35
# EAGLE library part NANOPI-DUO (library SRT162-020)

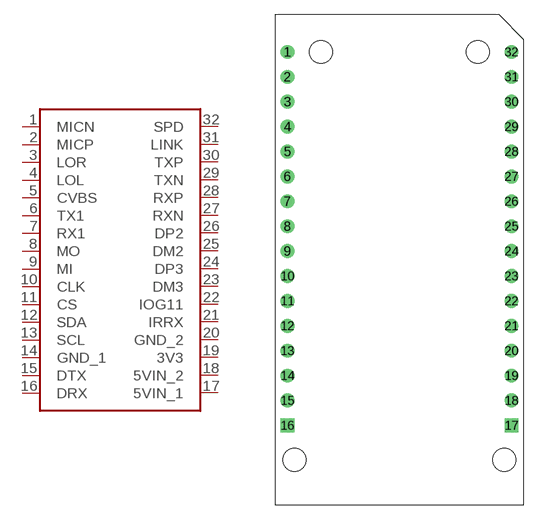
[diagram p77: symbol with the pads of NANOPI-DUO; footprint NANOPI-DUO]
Designator prefix M

## NANOPI-DUO  [NANOPI-DUO]
1  MICN
2  MICP
3  LOR
4  LOL
5  CVBS
6  TX1
7  RX1
8  MO
9  MI
10  CLK
11  CS
12  SDA
13  SCL
14  GND_1
15  DTX
16  DRX
17  5VIN_1
18  5VIN_2
19  3V3
20  GND_2
21  IRRX
22  IOG11
23  DM3
24  DP3
25  DM2
26  DP2
27  RXN
28  RXP
29  TXN
30  TXP
31  LINK
32  SPD

## Footprint NANOPI-DUO (pad centres in mm)
drill 0.9: 1 -10.16,10.16; 2 -10.16,7.62; 3 -10.16,5.08; 4 -10.16,2.54; 5 -10.16,0; 6 -10.16,-2.54; 7 -10.16,-5.08; 8 -10.16,-7.62; 9 -10.16,-10.16; 10 -10.16,-12.7; 11 -10.16,-15.24; 12 -10.16,-17.78; 13 -10.16,-20.32; 14 -10.16,-22.86; 15 -10.16,-25.4; 18 12.7,-25.4; 19 12.7,-22.86; 20 12.7,-20.32; 21 12.7,-17.78; 22 12.7,-15.24; 23 12.7,-12.7; 24 12.7,-10.16; 25 12.7,-7.62; 26 12.7,-5.08; 27 12.7,-2.54; 28 12.7,0; 29 12.7,2.54; 30 12.7,5.08; 31 12.7,7.62; 32 12.7,10.16
drill 0.9 square: 16 -10.16,-27.94; 17 12.7,-27.94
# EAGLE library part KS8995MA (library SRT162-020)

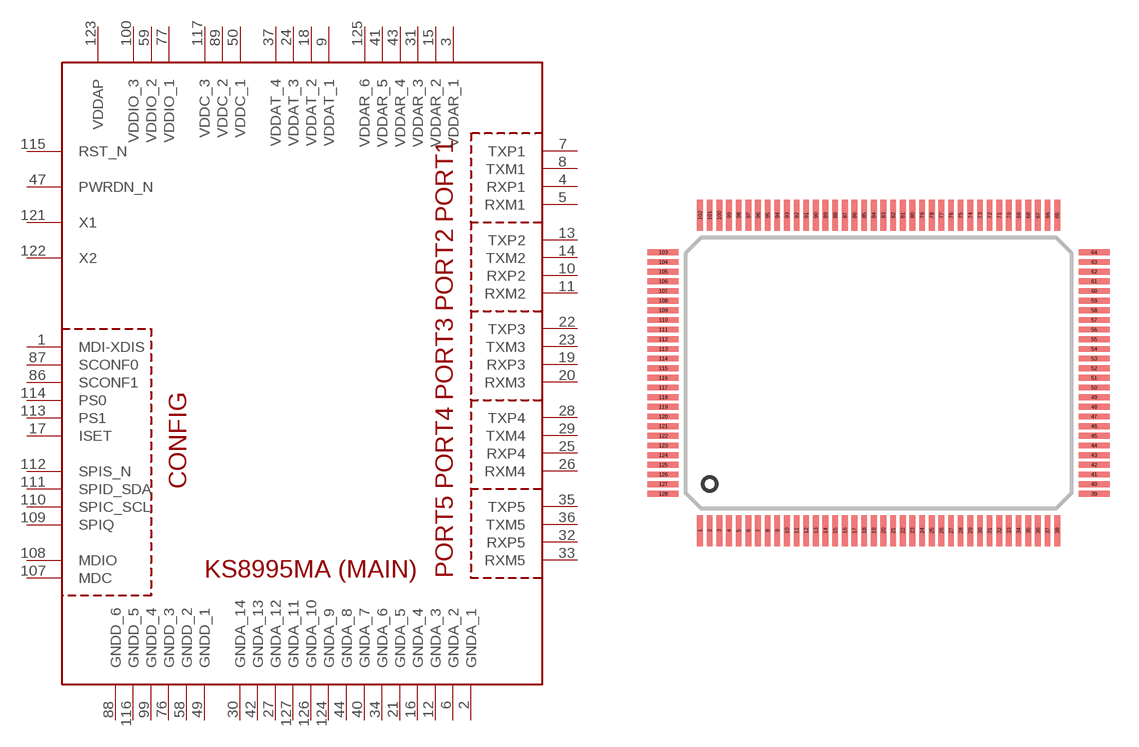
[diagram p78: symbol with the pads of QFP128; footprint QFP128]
Designator prefix U

## KS8995MA  [QFP128]
1  MDI-XDIS
2  GNDA_1
3  VDDAR_1
4  RXP1
5  RXM1
6  GNDA_2
7  TXP1
8  TXM1
9  VDDAT_1
10  RXP2
11  RXM2
12  GNDA_3
13  TXP2
14  TXM2
15  VDDAR_2
16  GNDA_4
17  ISET
18  VDDAT_2
19  RXP3
20  RXM3
21  GNDA_5
22  TXP3
23  TXM3
24  VDDAT_3
25  RXP4
26  RXM4
27  GNDA_12
28  TXP4
29  TXM4
30  GNDA_14
31  VDDAR_3
32  RXP5
33  RXM5
34  GNDA_6
35  TXP5
36  TXM5
37  VDDAT_4
40  GNDA_7
41  VDDAR_5
42  GNDA_13
43  VDDAR_4
44  GNDA_8
47  PWRDN_N
49  GNDD_1
50  VDDC_1
58  GNDD_2
59  VDDIO_2
76  GNDD_3
77  VDDIO_1
86  SCONF1
87  SCONF0
88  GNDD_6
89  VDDC_2
99  GNDD_4
100  VDDIO_3
107  MDC
108  MDIO
109  SPIQ
110  SPIC_SCL
111  SPID_SDA
112  SPIS_N
113  PS1
114  PS0
115  RST_N
116  GNDD_5
117  VDDC_3
121  X1
122  X2
123  VDDAP
124  GNDA_9
125  VDDAR_6
126  GNDA_10
127  GNDA_11

## Footprint QFP128 (pad centres in mm)
smd 0.3 x 1.6: 1 -9.25,-8.16; 2 -8.75,-8.16; 3 -8.25,-8.16; 4 -7.75,-8.16; 5 -7.25,-8.16; 6 -6.75,-8.16; 7 -6.25,-8.16; 8 -5.75,-8.16; 9 -5.25,-8.16; 10 -4.75,-8.16; 11 -4.25,-8.16; 12 -3.75,-8.16; 13 -3.25,-8.16; 14 -2.75,-8.16; 15 -2.25,-8.16; 16 -1.75,-8.16; 17 -1.25,-8.16; 18 -0.75,-8.16; 19 -0.25,-8.16; 20 0.25,-8.16; 21 0.75,-8.16; 22 1.25,-8.16; 23 1.75,-8.16; 24 2.25,-8.16; 25 2.75,-8.16; 26 3.25,-8.16; 27 3.75,-8.16; 28 4.25,-8.16; 29 4.75,-8.16; 30 5.25,-8.16; 31 5.75,-8.16; 32 6.25,-8.16; 33 6.75,-8.16; 34 7.25,-8.16; 35 7.75,-8.16; 36 8.25,-8.16; 37 8.75,-8.16; 38 9.25,-8.16; 65 9.25,8.16; 66 8.75,8.16; 67 8.25,8.16; 68 7.75,8.16; 69 7.25,8.16; 70 6.75,8.16; 71 6.25,8.16; 72 5.75,8.16; 73 5.25,8.16; 74 4.75,8.16; 75 4.25,8.16; 76 3.75,8.16; 77 3.25,8.16; 78 2.75,8.16; 79 2.25,8.16; 80 1.75,8.16; 81 1.25,8.16; 82 0.75,8.16; 83 0.25,8.16; 84 -0.25,8.16; 85 -0.75,8.16; 86 -1.25,8.16; 87 -1.75,8.16; 88 -2.25,8.16; 89 -2.75,8.16; 90 -3.25,8.16; 91 -3.75,8.16; 92 -4.25,8.16; 93 -4.75,8.16; 94 -5.25,8.16; 95 -5.75,8.16; 96 -6.25,8.16; 97 -6.75,8.16; 98 -7.25,8.16; 99 -7.75,8.16; 100 -8.25,8.16; 101 -8.75,8.16; 102 -9.25,8.16
smd 1.6 x 0.3: 39 11.16,-6.25; 40 11.16,-5.75; 41 11.16,-5.25; 42 11.16,-4.75; 43 11.16,-4.25; 44 11.16,-3.75; 45 11.16,-3.25; 46 11.16,-2.75; 47 11.16,-2.25; 48 11.16,-1.75; 49 11.16,-1.25; 50 11.16,-0.75; 51 11.16,-0.25; 52 11.16,0.25; 53 11.16,0.75; 54 11.16,1.25; 55 11.16,1.75; 56 11.16,2.25; 57 11.16,2.75; 58 11.16,3.25; 59 11.16,3.75; 60 11.16,4.25; 61 11.16,4.75; 62 11.16,5.25; 63 11.16,5.75; 64 11.16,6.25; 103 -11.16,6.25; 104 -11.16,5.75; 105 -11.16,5.25; 106 -11.16,4.75; 107 -11.16,4.25; 108 -11.16,3.75; 109 -11.16,3.25; 110 -11.16,2.75; 111 -11.16,2.25; 112 -11.16,1.75; 113 -11.16,1.25; 114 -11.16,0.75; 115 -11.16,0.25; 116 -11.16,-0.25; 117 -11.16,-0.75; 118 -11.16,-1.25; 119 -11.16,-1.75; 120 -11.16,-2.25; 121 -11.16,-2.75; 122 -11.16,-3.25; 123 -11.16,-3.75; 124 -11.16,-4.25; 125 -11.16,-4.75; 126 -11.16,-5.25; 127 -11.16,-5.75; 128 -11.16,-6.25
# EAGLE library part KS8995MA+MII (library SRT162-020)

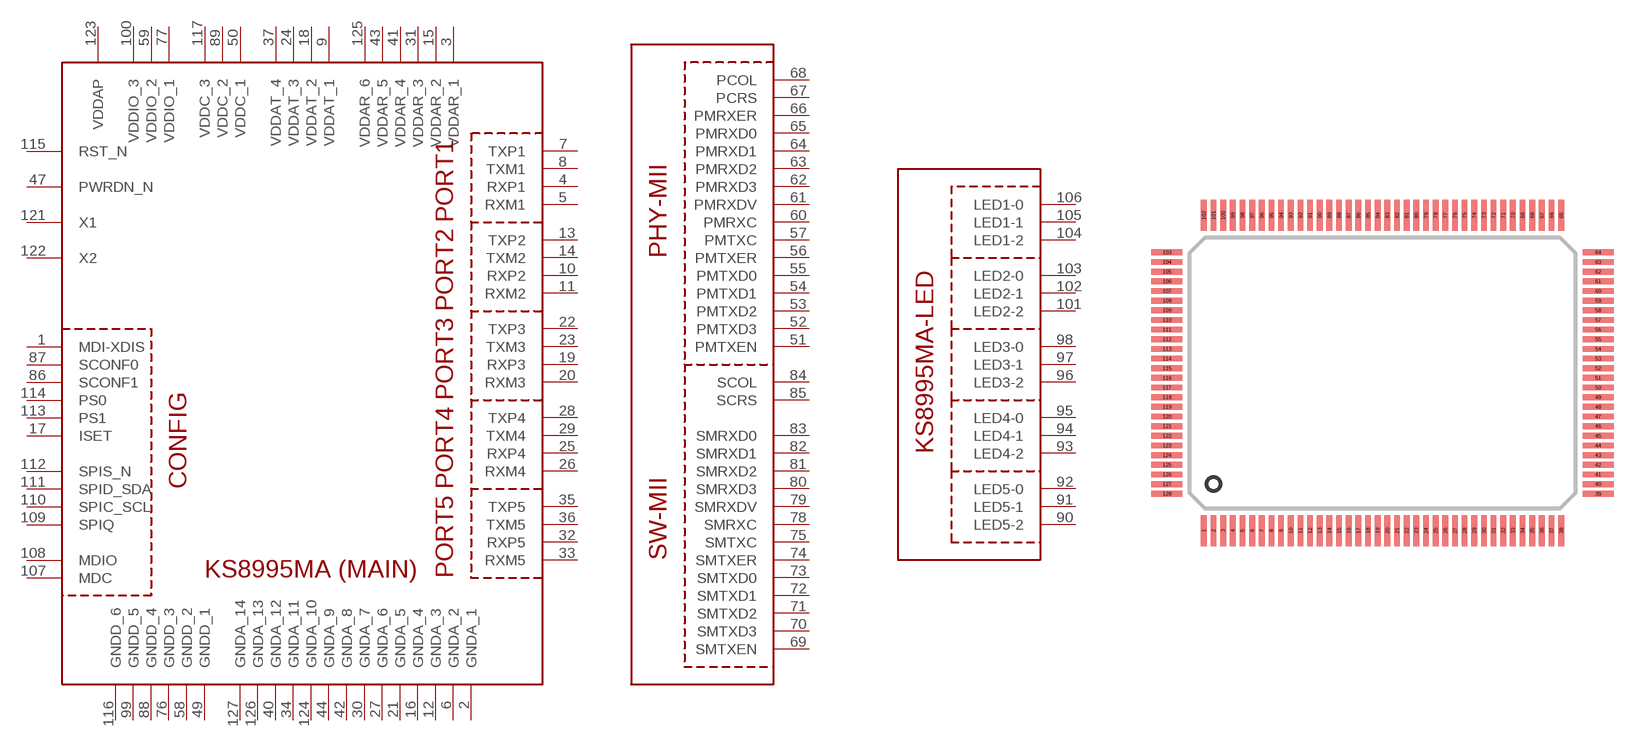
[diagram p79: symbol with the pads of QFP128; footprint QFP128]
Designator prefix U; gates G$1=KS8995MA_MAIN G$2=KS8995MA_MII G$3=KS8995MA_LED

## KS8995MA+MII  [QFP128]
1  G$1:MDI-XDIS
2  G$1:GNDA_1
3  G$1:VDDAR_1
4  G$1:RXP1
5  G$1:RXM1
6  G$1:GNDA_2
7  G$1:TXP1
8  G$1:TXM1
9  G$1:VDDAT_1
10  G$1:RXP2
11  G$1:RXM2
12  G$1:GNDA_3
13  G$1:TXP2
14  G$1:TXM2
15  G$1:VDDAR_2
16  G$1:GNDA_4
17  G$1:ISET
18  G$1:VDDAT_2
19  G$1:RXP3
20  G$1:RXM3
21  G$1:GNDA_5
22  G$1:TXP3
23  G$1:TXM3
24  G$1:VDDAT_3
25  G$1:RXP4
26  G$1:RXM4
27  G$1:GNDA_6
28  G$1:TXP4
29  G$1:TXM4
30  G$1:GNDA_7
31  G$1:VDDAR_3
32  G$1:RXP5
33  G$1:RXM5
34  G$1:GNDA_11
35  G$1:TXP5
36  G$1:TXM5
37  G$1:VDDAT_4
40  G$1:GNDA_12
41  G$1:VDDAR_4
42  G$1:GNDA_8
43  G$1:VDDAR_5
44  G$1:GNDA_9
47  G$1:PWRDN_N
49  G$1:GNDD_1
50  G$1:VDDC_1
51  G$2:PMTXEN
52  G$2:PMTXD3
53  G$2:PMTXD2
54  G$2:PMTXD1
55  G$2:PMTXD0
56  G$2:PMTXER
57  G$2:PMTXC
58  G$1:GNDD_2
59  G$1:VDDIO_2
60  G$2:PMRXC
61  G$2:PMRXDV
62  G$2:PMRXD3
63  G$2:PMRXD2
64  G$2:PMRXD1
65  G$2:PMRXD0
66  G$2:PMRXER
67  G$2:PCRS
68  G$2:PCOL
69  G$2:SMTXEN
70  G$2:SMTXD3
71  G$2:SMTXD2
72  G$2:SMTXD1
73  G$2:SMTXD0
74  G$2:SMTXER
75  G$2:SMTXC
76  G$1:GNDD_3
77  G$1:VDDIO_1
78  G$2:SMRXC
79  G$2:SMRXDV
80  G$2:SMRXD3
81  G$2:SMRXD2
82  G$2:SMRXD1
83  G$2:SMRXD0
84  G$2:SCOL
85  G$2:SCRS
86  G$1:SCONF1
87  G$1:SCONF0
88  G$1:GNDD_4
89  G$1:VDDC_2
90  G$3:LED5-2
91  G$3:LED5-1
92  G$3:LED5-0
93  G$3:LED4-2
94  G$3:LED4-1
95  G$3:LED4-0
96  G$3:LED3-2
97  G$3:LED3-1
98  G$3:LED3-0
99  G$1:GNDD_5
100  G$1:VDDIO_3
101  G$3:LED2-2
102  G$3:LED2-1
103  G$3:LED2-0
104  G$3:LED1-2
105  G$3:LED1-1
106  G$3:LED1-0
107  G$1:MDC
108  G$1:MDIO
109  G$1:SPIQ
110  G$1:SPIC_SCL
111  G$1:SPID_SDA
112  G$1:SPIS_N
113  G$1:PS1
114  G$1:PS0
115  G$1:RST_N
116  G$1:GNDD_6
117  G$1:VDDC_3
121  G$1:X1
122  G$1:X2
123  G$1:VDDAP
124  G$1:GNDA_10
125  G$1:VDDAR_6
126  G$1:GNDA_13
127  G$1:GNDA_14

## Footprint QFP128 (pad centres in mm)
smd 0.3 x 1.6: 1 -9.25,-8.16; 2 -8.75,-8.16; 3 -8.25,-8.16; 4 -7.75,-8.16; 5 -7.25,-8.16; 6 -6.75,-8.16; 7 -6.25,-8.16; 8 -5.75,-8.16; 9 -5.25,-8.16; 10 -4.75,-8.16; 11 -4.25,-8.16; 12 -3.75,-8.16; 13 -3.25,-8.16; 14 -2.75,-8.16; 15 -2.25,-8.16; 16 -1.75,-8.16; 17 -1.25,-8.16; 18 -0.75,-8.16; 19 -0.25,-8.16; 20 0.25,-8.16; 21 0.75,-8.16; 22 1.25,-8.16; 23 1.75,-8.16; 24 2.25,-8.16; 25 2.75,-8.16; 26 3.25,-8.16; 27 3.75,-8.16; 28 4.25,-8.16; 29 4.75,-8.16; 30 5.25,-8.16; 31 5.75,-8.16; 32 6.25,-8.16; 33 6.75,-8.16; 34 7.25,-8.16; 35 7.75,-8.16; 36 8.25,-8.16; 37 8.75,-8.16; 38 9.25,-8.16; 65 9.25,8.16; 66 8.75,8.16; 67 8.25,8.16; 68 7.75,8.16; 69 7.25,8.16; 70 6.75,8.16; 71 6.25,8.16; 72 5.75,8.16; 73 5.25,8.16; 74 4.75,8.16; 75 4.25,8.16; 76 3.75,8.16; 77 3.25,8.16; 78 2.75,8.16; 79 2.25,8.16; 80 1.75,8.16; 81 1.25,8.16; 82 0.75,8.16; 83 0.25,8.16; 84 -0.25,8.16; 85 -0.75,8.16; 86 -1.25,8.16; 87 -1.75,8.16; 88 -2.25,8.16; 89 -2.75,8.16; 90 -3.25,8.16; 91 -3.75,8.16; 92 -4.25,8.16; 93 -4.75,8.16; 94 -5.25,8.16; 95 -5.75,8.16; 96 -6.25,8.16; 97 -6.75,8.16; 98 -7.25,8.16; 99 -7.75,8.16; 100 -8.25,8.16; 101 -8.75,8.16; 102 -9.25,8.16
smd 1.6 x 0.3: 39 11.16,-6.25; 40 11.16,-5.75; 41 11.16,-5.25; 42 11.16,-4.75; 43 11.16,-4.25; 44 11.16,-3.75; 45 11.16,-3.25; 46 11.16,-2.75; 47 11.16,-2.25; 48 11.16,-1.75; 49 11.16,-1.25; 50 11.16,-0.75; 51 11.16,-0.25; 52 11.16,0.25; 53 11.16,0.75; 54 11.16,1.25; 55 11.16,1.75; 56 11.16,2.25; 57 11.16,2.75; 58 11.16,3.25; 59 11.16,3.75; 60 11.16,4.25; 61 11.16,4.75; 62 11.16,5.25; 63 11.16,5.75; 64 11.16,6.25; 103 -11.16,6.25; 104 -11.16,5.75; 105 -11.16,5.25; 106 -11.16,4.75; 107 -11.16,4.25; 108 -11.16,3.75; 109 -11.16,3.25; 110 -11.16,2.75; 111 -11.16,2.25; 112 -11.16,1.75; 113 -11.16,1.25; 114 -11.16,0.75; 115 -11.16,0.25; 116 -11.16,-0.25; 117 -11.16,-0.75; 118 -11.16,-1.25; 119 -11.16,-1.75; 120 -11.16,-2.25; 121 -11.16,-2.75; 122 -11.16,-3.25; 123 -11.16,-3.75; 124 -11.16,-4.25; 125 -11.16,-4.75; 126 -11.16,-5.25; 127 -11.16,-5.75; 128 -11.16,-6.25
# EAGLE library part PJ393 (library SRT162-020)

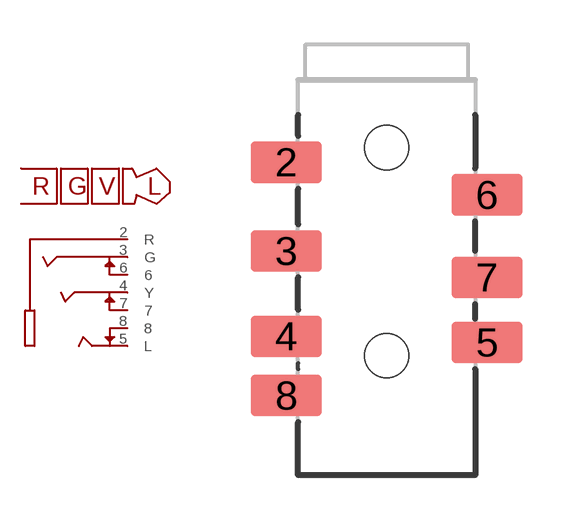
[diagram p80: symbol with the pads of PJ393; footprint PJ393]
Designator prefix CON

## PJ393  [PJ393]
2  R
3  G
4  Y
5  L
6  6
7  7
8  8

## Footprint PJ393 (pad centres in mm)
smd 2.4 x 1.4: 2 -3.4,-2.8; 3 -3.4,-5.8; 4 -3.4,-8.7; 5 3.4,-8.9; 6 3.4,-3.9; 7 3.4,-6.7; 8 -3.4,-10.7
hole 1.5 at 0,-2.3
hole 1.5 at 0,-9.35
